One B-rep face of a CAD part: STEP entity #178.
In plain terms, the planar face has unit normal (1, 0, 0).
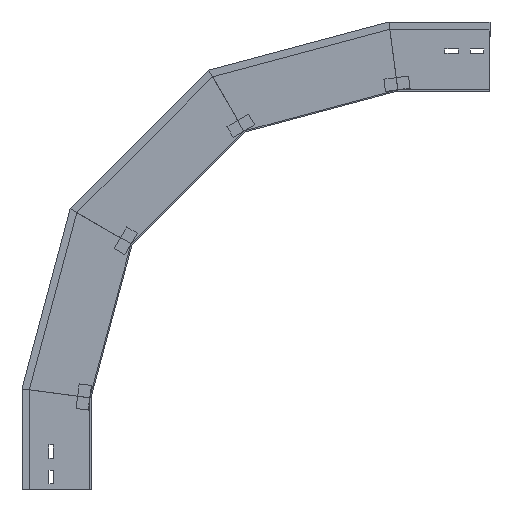
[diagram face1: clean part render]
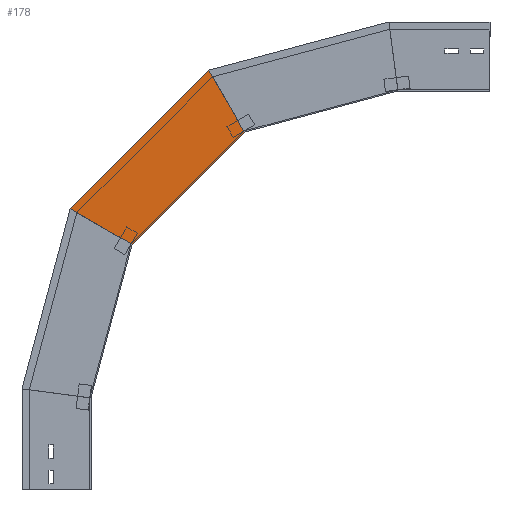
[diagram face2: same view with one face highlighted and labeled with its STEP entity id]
Its self-contained STEP definition (entity closure, numbers rounded to 3 decimals):
#42 = DIRECTION ( 'NONE',  ( 0., 0., -1. ) ) ;
#69 = VERTEX_POINT ( 'NONE', #426 ) ;
#121 = LINE ( 'NONE', #1741, #162 ) ;
#162 = VECTOR ( 'NONE', #1597, 1000. ) ;
#171 = VERTEX_POINT ( 'NONE', #793 ) ;
#178 = ADVANCED_FACE ( 'NONE', ( #914 ), #1357, .T. ) ;
#226 = LINE ( 'NONE', #524, #1382 ) ;
#381 = DIRECTION ( 'NONE',  ( 0., -0.866, -0.5 ) ) ;
#384 = ORIENTED_EDGE ( 'NONE', *, *, #1047, .T. ) ;
#400 = CARTESIAN_POINT ( 'NONE',  ( 0., 36.033, 456.207 ) ) ;
#426 = CARTESIAN_POINT ( 'NONE',  ( 0., -250.175, 583.315 ) ) ;
#524 = CARTESIAN_POINT ( 'NONE',  ( 0., -128.762, 364.536 ) ) ;
#585 = AXIS2_PLACEMENT_3D ( 'NONE', #1508, #611, #42 ) ;
#611 = DIRECTION ( 'NONE',  ( 1., 0., 0. ) ) ;
#621 = LINE ( 'NONE', #1208, #1652 ) ;
#698 = LINE ( 'NONE', #400, #907 ) ;
#711 = ORIENTED_EDGE ( 'NONE', *, *, #844, .F. ) ;
#793 = CARTESIAN_POINT ( 'NONE',  ( 0., -191.941, 684.18 ) ) ;
#815 = ORIENTED_EDGE ( 'NONE', *, *, #1118, .F. ) ;
#844 = EDGE_CURVE ( 'NONE', #948, #69, #121, .T. ) ;
#856 = DIRECTION ( 'NONE',  ( 0., -0.707, 0.707 ) ) ;
#907 = VECTOR ( 'NONE', #856, 1000. ) ;
#914 = FACE_OUTER_BOUND ( 'NONE', #1812, .T. ) ;
#924 = VERTEX_POINT ( 'NONE', #1876 ) ;
#948 = VERTEX_POINT ( 'NONE', #1798 ) ;
#1047 = EDGE_CURVE ( 'NONE', #171, #69, #621, .T. ) ;
#1118 = EDGE_CURVE ( 'NONE', #924, #948, #226, .T. ) ;
#1208 = CARTESIAN_POINT ( 'NONE',  ( 0., -287.996, 517.807 ) ) ;
#1357 = PLANE ( 'NONE',  #585 ) ;
#1382 = VECTOR ( 'NONE', #381, 1000. ) ;
#1508 = CARTESIAN_POINT ( 'NONE',  ( 0., -43.517, 376.657 ) ) ;
#1592 = ORIENTED_EDGE ( 'NONE', *, *, #1632, .T. ) ;
#1597 = DIRECTION ( 'NONE',  ( 0., -0.707, 0.707 ) ) ;
#1632 = EDGE_CURVE ( 'NONE', #924, #171, #698, .T. ) ;
#1652 = VECTOR ( 'NONE', #1790, 1000. ) ;
#1741 = CARTESIAN_POINT ( 'NONE',  ( 0., -43.517, 376.657 ) ) ;
#1790 = DIRECTION ( 'NONE',  ( 0., -0.5, -0.866 ) ) ;
#1798 = CARTESIAN_POINT ( 'NONE',  ( 0., -67.034, 400.175 ) ) ;
#1812 = EDGE_LOOP ( 'NONE', ( #1592, #384, #711, #815 ) ) ;
#1876 = CARTESIAN_POINT ( 'NONE',  ( 0., 33.831, 458.409 ) ) ;
